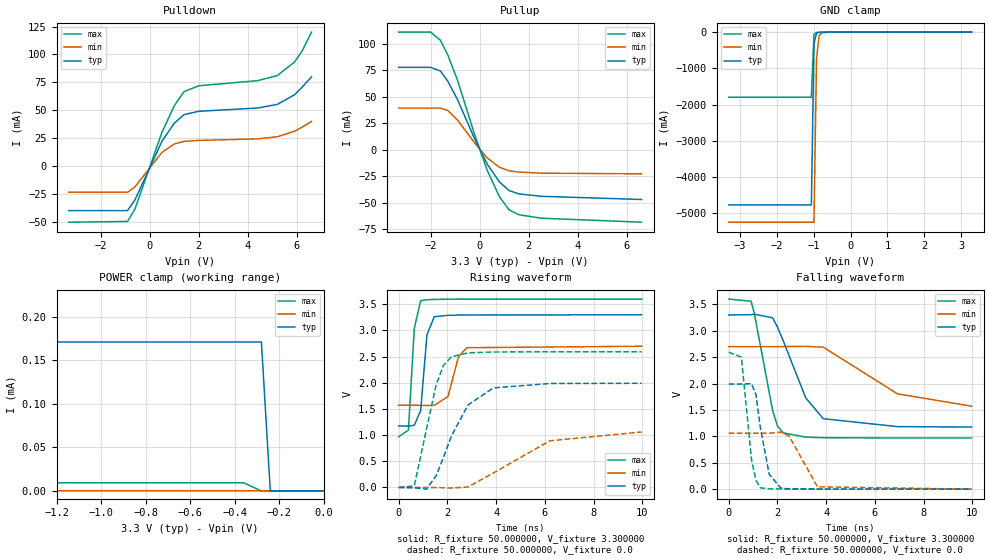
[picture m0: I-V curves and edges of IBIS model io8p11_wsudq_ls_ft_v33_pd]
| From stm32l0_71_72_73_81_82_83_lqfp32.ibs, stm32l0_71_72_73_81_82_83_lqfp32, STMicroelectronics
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|   Model io8p11_wsudq_ls_ft_v33_pd
[Model]  io8p11_wsudq_ls_ft_v33_pd
Model_type I/O
Polarity   Non-Inverting
Enable   Active-Low
Vinl =   0.990000V
Vinh =   2.310000V
Vmeas =  1.650000V
Cref =   50.000000pF
Rref =   100.000000M
Vref =   0.0V
C_comp   2.653200pF   2.620200pF   2.695100pF
[Temperature Range]   25.000000   0.125000k   -40.000000
[Pullup Reference]   3.300000V   2.700000V   3.600000V
[Pulldown Reference]   0.0V   0.0V   0.0V
[POWER Clamp Reference]   3.300000V   2.700000V   3.600000V
[GND Clamp Reference]   0.0V   0.0V   0.0V
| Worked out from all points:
|   slope of the pulldown table from 0 to 0.495 V, typ, clamps not added: 22.6 ohm
|   slope of the pullup table from 0 to 0.495 V, typ, clamps not added: 23.9 ohm
|   GND clamp passes 1 mA (typ) near -0.64 V on its own axis
|   POWER clamp passes 1 mA (typ) near -2.99 V on its own axis
|   rising waveform, R_fixture 50.000000, V_fixture 3.300000: 20-80 % time 216ps typ, 361ps min, 180ps max; typ from 1.18 V to 3.3 V
|   rising waveform, R_fixture 50.000000, V_fixture 0.0: 20-80 % time 1.18ns typ, 2.22ns min, 704ps max; typ from 0 V to 1.99 V
|   falling waveform, R_fixture 50.000000, V_fixture 3.300000: 20-80 % time 1.13ns typ, 2.14ns min, 648ps max; typ from 3.3 V to 1.18 V
|   falling waveform, R_fixture 50.000000, V_fixture 0.0: 20-80 % time 400ps typ, 570ps min, 321ps max; typ from 1.99 V to 0 V
[Pulldown]
|Voltage   I(typ)   I(min)   I(max)
-3.3V     -39.83mA   -23.37mA   -50.2mA
-900mV    -39.83mA   -23.37mA   -49.53mA
-600mV    -30.28mA   -18.59mA   -38.45mA
500mV     22.11mA    12.28mA    30.1mA
1V        38.33mA    19.81mA    53.88mA
1.4V      46.1mA     22.18mA    66.72mA
2V        49.07mA    23.02mA    71.93mA
4.4V      52.05mA    24.38mA    76.53mA
5.2V      55.25mA    26.31mA    81.02mA
5.9V      63.83mA    31.17mA    93.18mA
6.2V      70.39mA    34.76mA    102.6mA
6.6V      80mA       40mA       120mA
[Pullup]
|Voltage   I(typ)   I(min)   I(max)
-3.3V     77.63mA    39.16mA    110.9mA
-2V       77.63mA    39.16mA    110.9mA
-1.6V     74.23mA    39.16mA    103.2mA
-1.3V     64.67mA    36.99mA    89.45mA
-900mV    47.14mA    27.83mA    65.38mA
-200mV    9.95mA     6.209mA    13.84mA
300mV     -13.29mA   -7.65mA    -18.99mA
800mV     -30.32mA   -16.54mA   -44.19mA
1.2V      -38.62mA   -19.99mA   -56.79mA
1.6V      -41.74mA   -21.17mA   -61.39mA
2.5V      -43.99mA   -22.16mA   -64.64mA
6.6V      -47mA      -22.8mA    -68.41mA
[GND_clamp]
|Voltage   I(typ)   I(min)   I(max)
-3.3V     -4.766A    -5.244A    -1.797A
-1.06V    -4.766A    -5.244A    -1.797A
-990mV    -326.8mA   -5.244A    -68.06mA
-920mV    -29.1mA    -722.2mA   -11.17mA
-850mV    -6.81mA    -104.4mA   -6.691mA
-780mV    -3.567mA   -17.46mA   -4.273mA
-500mV    -68.7uA    -184.5uA   -41.56uA
3.28V     73.95uA    88.62uA    51.48uA
[POWER_clamp]
|Voltage   I(typ)   I(min)   I(max)
-3.28V    3.05A      15.65uA    3.723A
-3.2V     3.05A      1.687uA    3.723A
-2.96V    269.4uA    209.1nA    3.723A
-2.92V    170.9uA    209.1nA    508.5mA
-2.8V     170.9uA    209.1nA    1.296mA
-2.76V    170.9uA    209.1nA    177.1uA
-2.72V    170.9uA    209.1nA    24.25uA
-2.68V    170.9uA    209.1nA    9.362uA
-360mV    170.9uA    209.1nA    9.362uA
-280mV    170.9uA    209.1nA    0A
-240mV    0A         209.1nA    0A
0V        0A         0A         0A
[Ramp]
| variable   typ   min   max
dV/dt_r  1.19382/1.17599n   0.62568/2.18277n   1.55514/0.70260n
dV/dt_f  1.27296/1.12815n   0.63348/2.06629n   1.57832/0.64667n
R_load = 50.000000
[Rising Waveform]
R_fixture= 50.000000
V_fixture= 3.300000
V_fixture_min= 2.700000
V_fixture_max= 3.600000
|time   V(typ)   V(min)   V(max)
0s        1.176V     1.571V     968.2mV
400.4ps   1.172V     1.571V     1.097V
640.6ps   1.189V     1.571V     3.037V
900.9ps   1.466V     1.569V     3.567V
1.161ns   2.918V     1.566V     3.586V
1.461ns   3.262V     1.569V     3.592V
2.022ns   3.288V     1.736V     3.597V
2.462ns   3.293V     2.506V     3.598V
2.803ns   3.295V     2.67V      3.599V
9.97ns    3.299V     2.698V     3.599V
[Rising Waveform]
R_fixture= 50.000000
V_fixture= 0.0
V_fixture_min= 0.0
V_fixture_max= 0.0
|time   V(typ)   V(min)   V(max)
0s        233.4uV    13.27uV    8.596uV
640.6ps   -5.596mV   200.2uV    30.64mV
1.141ns   -32.41mV   47.52uV    1.115V
1.542ns   226.3mV    -1.962mV   1.968V
1.842ns   580.6mV    -5.494mV   2.335V
2.162ns   980.9mV    -11.14mV   2.495V
2.843ns   1.575V     9.284mV    2.571V
3.884ns   1.902V     276.1mV    2.588V
6.206ns   1.986V     891.5mV    2.592V
9.97ns    1.99V      1.06V      2.592V
[Falling Waveform]
R_fixture= 50.000000
V_fixture= 3.300000
V_fixture_min= 2.700000
V_fixture_max= 3.600000
|time   V(typ)   V(min)   V(max)
0s        3.299V     2.698V     3.599V
920.9ps   3.303V     2.698V     3.558V
1.061ns   3.312V     2.698V     3.309V
1.802ns   3.244V     2.698V     1.494V
2.002ns   3.071V     2.698V     1.196V
2.242ns   2.806V     2.7V       1.065V
3.163ns   1.727V     2.703V     985.1mV
3.884ns   1.334V     2.688V     974.3mV
6.927ns   1.184V     1.805V     968.4mV
9.97ns    1.176V     1.571V     968.2mV
[Falling Waveform]
R_fixture= 50.000000
V_fixture= 0.0
V_fixture_min= 0.0
V_fixture_max= 0.0
|time   V(typ)   V(min)   V(max)
0s        1.99V      1.06V      2.592V
520.5ps   1.99V      1.06V      2.5V
940.9ps   1.998V     1.06V      545.9mV
1.121ns   1.784V     1.06V      164.5mV
1.301ns   1.163V     1.06V      25.5mV
1.662ns   283.7mV    1.06V      6.072mV
2.142ns   20.28mV    1.08V      3.796mV
2.482ns   6.663mV    1.004V     2.722mV
3.644ns   2.629mV    44.18mV    753uV
9.97ns    233.4uV    13.27uV    8.596uV
